VERSION 5.7 ;
  NOWIREEXTENSIONATPIN ON ;
  DIVIDERCHAR "/" ;
  BUSBITCHARS "[]" ;
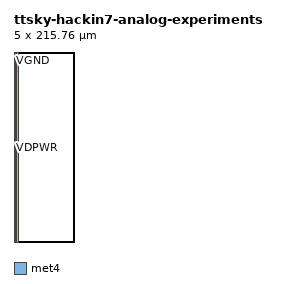
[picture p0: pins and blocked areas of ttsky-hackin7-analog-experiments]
MACRO ttsky-hackin7-analog-experiments
  CLASS BLOCK ;
  FOREIGN ttsky-hackin7-analog-experiments ;
  ORIGIN -1.000 -5.000 ;
  SIZE 5.000 BY 215.760 ;
  PIN VDPWR
    DIRECTION INOUT ;
    USE POWER ;
    PORT
      LAYER met4 ;
        RECT 1.930 5.000 3.000 220.760 ;
    END
  END VDPWR
  PIN VGND
    DIRECTION INOUT ;
    USE GROUND ;
    PORT
      LAYER met4 ;
        RECT 4.000 5.000 6.000 220.760 ;
    END
  END VGND
  OBS
      LAYER met4 ;
        RECT 1.000 215.820 1.930 220.760 ;
  END
END ttsky-hackin7-analog-experiments
END LIBRARY

